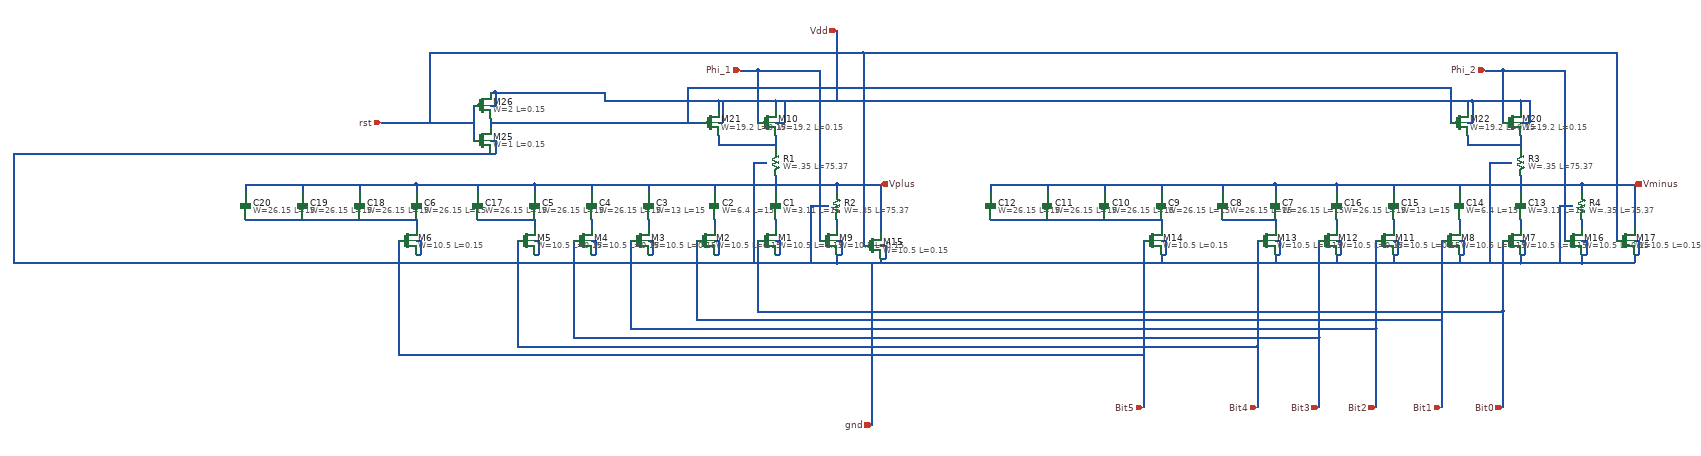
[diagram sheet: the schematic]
v {xschem version=3.4.6 file_version=1.2}
G {}
K {}
V {}
S {}
E {}
N -60 30 -60 70 {lab=Vplus}
N -200 50 -200 70 {lab=Vplus}
N -350 50 -350 70 {lab=Vplus}
N -480 50 -480 70 {lab=Vplus}
N -60 130 -60 150 {lab=#net1}
N -60 180 -50 180 {lab=gnd}
N -50 180 -50 210 {lab=gnd}
N -60 210 -50 210 {lab=gnd}
N -200 130 -200 150 {lab=#net2}
N -200 180 -190 180 {lab=gnd}
N -190 180 -190 210 {lab=gnd}
N -200 210 -190 210 {lab=gnd}
N -350 130 -350 150 {lab=#net3}
N -350 180 -340 180 {lab=gnd}
N -340 180 -340 210 {lab=gnd}
N -350 210 -340 210 {lab=gnd}
N -480 130 -480 150 {lab=#net4}
N -480 180 -470 180 {lab=gnd}
N -470 180 -470 210 {lab=gnd}
N -480 210 -470 210 {lab=gnd}
N -1060 230 -60 230 {lab=gnd}
N -60 230 80 230 {lab=gnd}
N 80 210 80 230 {lab=gnd}
N 80 210 90 210 {lab=gnd}
N 90 180 90 210 {lab=gnd}
N 80 180 90 180 {lab=gnd}
N 80 130 80 150 {lab=#net5}
N -520 180 -520 320 {lab=Bit3}
N -390 180 -390 320 {lab=Bit2}
N -240 180 -240 320 {lab=Bit1}
N -100 180 -100 320 {lab=Bit0}
N 80 50 80 70 {lab=Vplus}
N -60 50 80 50 {lab=Vplus}
N -60 -60 -60 -30 {lab=#net6}
N -60 -140 -60 -120 {lab=Vdd}
N 1640 30 1640 70 {lab=Vminus}
N 1500 50 1500 70 {lab=Vminus}
N 1350 50 1350 70 {lab=Vminus}
N 1220 50 1220 70 {lab=Vminus}
N 1640 130 1640 150 {lab=#net7}
N 1640 180 1650 180 {lab=gnd}
N 1650 180 1650 210 {lab=gnd}
N 1640 210 1650 210 {lab=gnd}
N 1500 130 1500 150 {lab=#net8}
N 1500 180 1510 180 {lab=gnd}
N 1510 180 1510 210 {lab=gnd}
N 1500 210 1510 210 {lab=gnd}
N 1350 130 1350 150 {lab=#net9}
N 1350 180 1360 180 {lab=gnd}
N 1360 180 1360 210 {lab=gnd}
N 1350 210 1360 210 {lab=gnd}
N 1220 130 1220 150 {lab=#net10}
N 1220 180 1230 180 {lab=gnd}
N 1230 180 1230 210 {lab=gnd}
N 1220 210 1230 210 {lab=gnd}
N 640 230 1640 230 {lab=gnd}
N 1220 210 1220 230 {lab=gnd}
N 1350 210 1350 230 {lab=gnd}
N 1500 210 1500 230 {lab=gnd}
N 1640 210 1640 230 {lab=gnd}
N 1640 230 1780 230 {lab=gnd}
N 1780 210 1780 230 {lab=gnd}
N 1780 210 1790 210 {lab=gnd}
N 1790 180 1790 210 {lab=gnd}
N 1780 180 1790 180 {lab=gnd}
N 1780 130 1780 150 {lab=#net11}
N 1180 180 1180 320 {lab=Bit3}
N 1310 180 1310 320 {lab=Bit2}
N 1460 180 1460 320 {lab=Bit1}
N 1600 180 1600 320 {lab=Bit0}
N 1780 50 1780 70 {lab=Vminus}
N 1640 50 1780 50 {lab=Vminus}
N 1640 -60 1640 -30 {lab=#net12}
N 1640 -140 1640 -120 {lab=Vdd}
N 80 230 300 230 {lab=gnd}
N -60 -140 1300 -140 {lab=Vdd}
N 80 -300 80 -140 {lab=Vdd}
N 160 230 160 560 {lab=gnd}
N 1600 320 1600 340 {lab=Bit0}
N -100 340 1260 340 {lab=Bit0}
N -100 320 -100 340 {lab=Bit0}
N 1460 320 1460 360 {lab=Bit1}
N -240 360 1120 360 {lab=Bit1}
N -240 320 -240 360 {lab=Bit1}
N 1310 320 1310 380 {lab=Bit2}
N -390 380 970 380 {lab=Bit2}
N -390 320 -390 380 {lab=Bit2}
N 1180 320 1180 400 {lab=Bit3}
N -520 400 840 400 {lab=Bit3}
N -520 320 -520 400 {lab=Bit3}
N 1180 400 1180 560 {lab=Bit3}
N 1310 380 1310 560 {lab=Bit2}
N 1460 360 1460 560 {lab=Bit1}
N 1600 340 1600 560 {lab=Bit0}
N 160 560 160 600 {lab=gnd}
N -60 -90 -40 -90 {lab=Vdd}
N -40 -140 -40 -90 {lab=Vdd}
N 1640 -90 1660 -90 {lab=Vdd}
N 1660 -140 1660 -90 {lab=Vdd}
N 1640 -140 1660 -140 {lab=Vdd}
N 1600 -210 1600 -90 {lab=Phi_2}
N 1600 -210 1740 -210 {lab=Phi_2}
N 1740 -210 1740 180 {lab=Phi_2}
N 1560 -210 1600 -210 {lab=Phi_2}
N 40 -210 40 180 {lab=Phi_1}
N -100 -210 40 -210 {lab=Phi_1}
N -100 -210 -100 -100 {lab=Phi_1}
N -140 -210 -100 -210 {lab=Phi_1}
N -100 -100 -100 -90 {lab=Phi_1}
N -110 -0 -80 -0 {lab=gnd}
N 20 100 60 100 {lab=gnd}
N 1730 100 1760 100 {lab=gnd}
N 1730 100 1730 230 {lab=gnd}
N 1570 0 1620 0 {lab=gnd}
N 1520 -140 1520 -120 {lab=Vdd}
N 1520 -90 1530 -90 {lab=Vdd}
N 1530 -140 1530 -90 {lab=Vdd}
N 1520 -60 1520 -40 {lab=#net12}
N 1520 -40 1640 -40 {lab=#net12}
N -190 -140 -60 -140 {lab=Vdd}
N -190 -90 -180 -90 {lab=Vdd}
N -180 -140 -180 -90 {lab=Vdd}
N -190 -140 -190 -120 {lab=Vdd}
N -190 -40 -60 -40 {lab=#net6}
N -190 -60 -190 -40 {lab=#net6}
N -280 -90 -230 -90 {lab=#net13}
N -260 -170 1140 -170 {lab=#net13}
N 1480 -170 1480 -90 {lab=#net13}
N 180 220 180 230 {lab=gnd}
N 180 190 190 190 {lab=gnd}
N 190 190 190 220 {lab=gnd}
N 180 220 190 220 {lab=gnd}
N 80 50 180 50 {lab=Vplus}
N 180 50 180 160 {lab=Vplus}
N 140 -250 140 190 {lab=rst}
N -280 -250 140 -250 {lab=rst}
N 1780 230 1900 230 {lab=gnd}
N 1900 210 1900 230 {lab=gnd}
N 1900 210 1910 210 {lab=gnd}
N 1910 180 1910 210 {lab=gnd}
N 1900 180 1910 180 {lab=gnd}
N 1900 50 1900 150 {lab=Vminus}
N 1780 50 1900 50 {lab=Vminus}
N 1860 -250 1860 180 {lab=rst}
N 140 -250 1520 -250 {lab=rst}
N -750 -130 -750 -50 {lab=rst}
N -960 -90 -750 -90 {lab=rst}
N -850 -250 -280 -250 {lab=rst}
N -850 -250 -850 -90 {lab=rst}
N -710 -100 -710 -80 {lab=#net13}
N -710 -90 -280 -90 {lab=#net13}
N -710 -130 -700 -130 {lab=Vdd}
N -700 -160 -700 -130 {lab=Vdd}
N -710 -160 -700 -160 {lab=Vdd}
N -710 -50 -700 -50 {lab=gnd}
N -700 -50 -700 -20 {lab=gnd}
N -710 -20 -700 -20 {lab=gnd}
N -1190 230 -1060 230 {lab=gnd}
N -1800 -20 -1800 230 {lab=gnd}
N -1190 -20 -710 -20 {lab=gnd}
N -700 -160 -450 -160 {lab=Vdd}
N -450 -160 -450 -140 {lab=Vdd}
N -450 -140 -190 -140 {lab=Vdd}
N -260 -170 -260 -90 {lab=#net13}
N -1360 -20 -1190 -20 {lab=gnd}
N -1360 230 -1190 230 {lab=gnd}
N 300 230 640 230 {lab=gnd}
N 1520 -250 1860 -250 {lab=rst}
N 1140 -170 1480 -170 {lab=#net13}
N 1300 -140 1530 -140 {lab=Vdd}
N 1530 -140 1640 -140 {lab=Vdd}
N 840 400 1180 400 {lab=Bit3}
N 970 380 1310 380 {lab=Bit2}
N 1120 360 1460 360 {lab=Bit1}
N 1260 340 1600 340 {lab=Bit0}
N -1800 -20 -1360 -20 {lab=gnd}
N -1800 230 -1360 230 {lab=gnd}
N 1220 50 1640 50 {lab=Vminus}
N -610 50 -610 70 {lab=Vplus}
N -600 50 -60 50 {lab=Vplus}
N -610 50 -600 50 {lab=Vplus}
N -610 180 -600 180 {lab=gnd}
N -600 180 -600 210 {lab=gnd}
N -610 210 -600 210 {lab=gnd}
N -610 130 -610 150 {lab=#net14}
N -650 180 -650 420 {lab=Bit4}
N -650 420 970 420 {lab=Bit4}
N 1080 50 1080 70 {lab=Vminus}
N 1080 180 1090 180 {lab=gnd}
N 1090 180 1090 210 {lab=gnd}
N 1080 210 1090 210 {lab=gnd}
N 1080 210 1080 230 {lab=gnd}
N 1080 130 1080 150 {lab=#net15}
N 1040 180 1040 420 {lab=Bit4}
N 970 420 1040 420 {lab=Bit4}
N 1040 420 1040 560 {lab=Bit4}
N 1080 50 1220 50 {lab=Vminus}
N -880 130 -880 150 {lab=#net16}
N -880 180 -870 180 {lab=gnd}
N -870 180 -870 210 {lab=gnd}
N -880 210 -870 210 {lab=gnd}
N -750 50 -610 50 {lab=Vplus}
N -880 50 -880 70 {lab=Vplus}
N -920 180 -920 440 {lab=Bit5}
N -790 440 690 440 {lab=Bit5}
N 1040 180 1040 420 {lab=Bit4}
N 820 130 820 150 {lab=#net17}
N 820 180 830 180 {lab=gnd}
N 830 180 830 210 {lab=gnd}
N 820 210 830 210 {lab=gnd}
N 820 210 820 230 {lab=gnd}
N 820 50 820 70 {lab=Vminus}
N 940 50 1080 50 {lab=Vminus}
N 960 50 960 70 {lab=Vminus}
N 960 130 1080 130 {lab=#net15}
N 430 130 820 130 {lab=#net17}
N 430 50 940 50 {lab=Vminus}
N 430 50 430 70 {lab=Vminus}
N 560 50 560 70 {lab=Vminus}
N 690 50 690 70 {lab=Vminus}
N 780 180 780 560 {lab=Bit5}
N 690 440 780 440 {lab=Bit5}
N -740 130 -610 130 {lab=#net14}
N -740 50 -740 70 {lab=Vplus}
N -920 440 -790 440 {lab=Bit5}
N -880 50 -750 50 {lab=Vplus}
N -1270 130 -880 130 {lab=#net16}
N -1270 50 -880 50 {lab=Vplus}
N -1270 50 -1270 70 {lab=Vplus}
N -1140 50 -1140 70 {lab=Vplus}
N -1010 50 -1010 70 {lab=Vplus}
N 1570 0 1570 230 {lab=gnd}
N -110 -0 -110 230 {lab=gnd}
N 20 100 20 230 {lab=gnd}
C {/usr/local/share/pdk/sky130A/libs.tech/xschem/sky130_fd_pr/cap_mim_m3_2.sym} -60 100 0 0 {name=C1 model=cap_mim_m3_2 W=3.11 L=15 MF=1 spiceprefix=X}
C {/usr/local/share/pdk/sky130A/libs.tech/xschem/sky130_fd_pr/cap_mim_m3_2.sym} -200 100 0 0 {name=C2 model=cap_mim_m3_2 W=6.4 L=15 MF=1 spiceprefix=X}
C {/usr/local/share/pdk/sky130A/libs.tech/xschem/sky130_fd_pr/cap_mim_m3_2.sym} -350 100 0 0 {name=C3 model=cap_mim_m3_2 W=13 L=15 MF=1 spiceprefix=X}
C {/usr/local/share/pdk/sky130A/libs.tech/xschem/sky130_fd_pr/cap_mim_m3_2.sym} -480 100 0 0 {name=C4 model=cap_mim_m3_2 W=26.15 L=15 MF=1 spiceprefix=X}
C {/usr/local/share/pdk/sky130A/libs.tech/xschem/sky130_fd_pr/nfet_01v8.sym} 60 180 0 0 {name=M9
W=10.5
L=0.15
nf=1 
mult=1
ad="'int((nf+1)/2) * W/nf * 0.29'" 
pd="'2*int((nf+1)/2) * (W/nf + 0.29)'"
as="'int((nf+2)/2) * W/nf * 0.29'" 
ps="'2*int((nf+2)/2) * (W/nf + 0.29)'"
nrd="'0.29 / W'" nrs="'0.29 / W'"
sa=0 sb=0 sd=0
model=nfet_01v8
spiceprefix=X
}
C {/usr/local/share/pdk/sky130A/libs.tech/xschem/sky130_fd_pr/pfet_01v8.sym} -80 -90 0 0 {name=M10
W=19.2
L=0.15
nf=1
mult=1
ad="'int((nf+1)/2) * W/nf * 0.29'" 
pd="'2*int((nf+1)/2) * (W/nf + 0.29)'"
as="'int((nf+2)/2) * W/nf * 0.29'" 
ps="'2*int((nf+2)/2) * (W/nf + 0.29)'"
nrd="'0.29 / W'" nrs="'0.29 / W'"
sa=0 sb=0 sd=0
model=pfet_01v8
spiceprefix=X
}
C {/usr/local/share/pdk/sky130A/libs.tech/xschem/sky130_fd_pr/pfet_01v8.sym} 1620 -90 0 0 {name=M20
W=19.2
L=0.15
nf=1
mult=1
ad="'int((nf+1)/2) * W/nf * 0.29'" 
pd="'2*int((nf+1)/2) * (W/nf + 0.29)'"
as="'int((nf+2)/2) * W/nf * 0.29'" 
ps="'2*int((nf+2)/2) * (W/nf + 0.29)'"
nrd="'0.29 / W'" nrs="'0.29 / W'"
sa=0 sb=0 sd=0
model=pfet_01v8
spiceprefix=X
}
C {opin.sym} 180 50 0 0 {name=p1 lab=Vplus}
C {opin.sym} 1900 50 0 0 {name=p2 lab=Vminus}
C {iopin.sym} 80 -300 0 0 {name=p3 lab=Vdd}
C {iopin.sym} 160 600 0 0 {name=p4 lab=gnd
}
C {ipin.sym} -140 -210 0 0 {name=p5 lab=Phi_1}
C {ipin.sym} 1560 -210 0 0 {name=p6 lab=Phi_2}
C {ipin.sym} 1600 560 0 0 {name=p7 lab=Bit0}
C {ipin.sym} 1460 560 0 0 {name=p8 lab=Bit1}
C {ipin.sym} 1310 560 0 0 {name=p9 lab=Bit2}
C {ipin.sym} 1180 560 0 0 {name=p10 lab=Bit3}
C {/usr/local/share/pdk/sky130A/libs.tech/xschem/sky130_fd_pr/pfet_01v8.sym} -210 -90 0 0 {name=M21
W=19.2
L=0.15
nf=1
mult=1
ad="'int((nf+1)/2) * W/nf * 0.29'" 
pd="'2*int((nf+1)/2) * (W/nf + 0.29)'"
as="'int((nf+2)/2) * W/nf * 0.29'" 
ps="'2*int((nf+2)/2) * (W/nf + 0.29)'"
nrd="'0.29 / W'" nrs="'0.29 / W'"
sa=0 sb=0 sd=0
model=pfet_01v8
spiceprefix=X
}
C {/usr/local/share/pdk/sky130A/libs.tech/xschem/sky130_fd_pr/pfet_01v8.sym} 1500 -90 0 0 {name=M22
W=19.2
L=0.15
nf=1
mult=1
ad="'int((nf+1)/2) * W/nf * 0.29'" 
pd="'2*int((nf+1)/2) * (W/nf + 0.29)'"
as="'int((nf+2)/2) * W/nf * 0.29'" 
ps="'2*int((nf+2)/2) * (W/nf + 0.29)'"
nrd="'0.29 / W'" nrs="'0.29 / W'"
sa=0 sb=0 sd=0
model=pfet_01v8
spiceprefix=X
}
C {/usr/local/share/pdk/sky130A/libs.tech/xschem/sky130_fd_pr/nfet_01v8.sym} -730 -50 0 0 {name=M25
W=1
L=0.15
nf=1 
mult=1
ad="'int((nf+1)/2) * W/nf * 0.29'" 
pd="'2*int((nf+1)/2) * (W/nf + 0.29)'"
as="'int((nf+2)/2) * W/nf * 0.29'" 
ps="'2*int((nf+2)/2) * (W/nf + 0.29)'"
nrd="'0.29 / W'" nrs="'0.29 / W'"
sa=0 sb=0 sd=0
model=nfet_01v8
spiceprefix=X
}
C {/usr/local/share/pdk/sky130A/libs.tech/xschem/sky130_fd_pr/pfet_01v8.sym} -730 -130 0 0 {name=M26
W=2
L=0.15
nf=1
mult=1
ad="'int((nf+1)/2) * W/nf * 0.29'" 
pd="'2*int((nf+1)/2) * (W/nf + 0.29)'"
as="'int((nf+2)/2) * W/nf * 0.29'" 
ps="'2*int((nf+2)/2) * (W/nf + 0.29)'"
nrd="'0.29 / W'" nrs="'0.29 / W'"
sa=0 sb=0 sd=0
model=pfet_01v8
spiceprefix=X
}
C {ipin.sym} -960 -90 0 0 {name=p15 lab=rst}
C {ipin.sym} 1040 560 0 0 {name=p11 lab=Bit4}
C {ipin.sym} 780 560 0 0 {name=p12 lab=Bit5}
C {/usr/local/share/pdk/sky130A/libs.tech/xschem/sky130_fd_pr/cap_mim_m3_2.sym} 1640 100 0 0 {name=C13 model=cap_mim_m3_2 W=3.11 L=15 MF=1 spiceprefix=X}
C {/usr/local/share/pdk/sky130A/libs.tech/xschem/sky130_fd_pr/cap_mim_m3_2.sym} 1500 100 0 0 {name=C14 model=cap_mim_m3_2 W=6.4 L=15 MF=1 spiceprefix=X}
C {/usr/local/share/pdk/sky130A/libs.tech/xschem/sky130_fd_pr/cap_mim_m3_2.sym} 1350 100 0 0 {name=C15 model=cap_mim_m3_2 W=13 L=15 MF=1 spiceprefix=X}
C {/usr/local/share/pdk/sky130A/libs.tech/xschem/sky130_fd_pr/cap_mim_m3_2.sym} 1220 100 0 0 {name=C16 model=cap_mim_m3_2 W=26.15 L=15 MF=1 spiceprefix=X}
C {/usr/local/share/pdk/sky130A/libs.tech/xschem/sky130_fd_pr/nfet_01v8.sym} -80 180 0 0 {name=M1
W=10.5
L=0.15
nf=1 
mult=1
ad="'int((nf+1)/2) * W/nf * 0.29'" 
pd="'2*int((nf+1)/2) * (W/nf + 0.29)'"
as="'int((nf+2)/2) * W/nf * 0.29'" 
ps="'2*int((nf+2)/2) * (W/nf + 0.29)'"
nrd="'0.29 / W'" nrs="'0.29 / W'"
sa=0 sb=0 sd=0
model=nfet_01v8
spiceprefix=X
}
C {/usr/local/share/pdk/sky130A/libs.tech/xschem/sky130_fd_pr/nfet_01v8.sym} -220 180 0 0 {name=M2
W=10.5
L=0.15
nf=1 
mult=1
ad="'int((nf+1)/2) * W/nf * 0.29'" 
pd="'2*int((nf+1)/2) * (W/nf + 0.29)'"
as="'int((nf+2)/2) * W/nf * 0.29'" 
ps="'2*int((nf+2)/2) * (W/nf + 0.29)'"
nrd="'0.29 / W'" nrs="'0.29 / W'"
sa=0 sb=0 sd=0
model=nfet_01v8
spiceprefix=X
}
C {/usr/local/share/pdk/sky130A/libs.tech/xschem/sky130_fd_pr/nfet_01v8.sym} -370 180 0 0 {name=M3
W=10.5
L=0.15
nf=1 
mult=1
ad="'int((nf+1)/2) * W/nf * 0.29'" 
pd="'2*int((nf+1)/2) * (W/nf + 0.29)'"
as="'int((nf+2)/2) * W/nf * 0.29'" 
ps="'2*int((nf+2)/2) * (W/nf + 0.29)'"
nrd="'0.29 / W'" nrs="'0.29 / W'"
sa=0 sb=0 sd=0
model=nfet_01v8
spiceprefix=X
}
C {/usr/local/share/pdk/sky130A/libs.tech/xschem/sky130_fd_pr/nfet_01v8.sym} -500 180 0 0 {name=M4
W=10.5
L=0.15
nf=1 
mult=1
ad="'int((nf+1)/2) * W/nf * 0.29'" 
pd="'2*int((nf+1)/2) * (W/nf + 0.29)'"
as="'int((nf+2)/2) * W/nf * 0.29'" 
ps="'2*int((nf+2)/2) * (W/nf + 0.29)'"
nrd="'0.29 / W'" nrs="'0.29 / W'"
sa=0 sb=0 sd=0
model=nfet_01v8
spiceprefix=X
}
C {/usr/local/share/pdk/sky130A/libs.tech/xschem/sky130_fd_pr/nfet_01v8.sym} -630 180 0 0 {name=M5
W=10.5
L=0.15
nf=1 
mult=1
ad="'int((nf+1)/2) * W/nf * 0.29'" 
pd="'2*int((nf+1)/2) * (W/nf + 0.29)'"
as="'int((nf+2)/2) * W/nf * 0.29'" 
ps="'2*int((nf+2)/2) * (W/nf + 0.29)'"
nrd="'0.29 / W'" nrs="'0.29 / W'"
sa=0 sb=0 sd=0
model=nfet_01v8
spiceprefix=X
}
C {/usr/local/share/pdk/sky130A/libs.tech/xschem/sky130_fd_pr/nfet_01v8.sym} -900 180 0 0 {name=M6
W=10.5
L=0.15
nf=1 
mult=1
ad="'int((nf+1)/2) * W/nf * 0.29'" 
pd="'2*int((nf+1)/2) * (W/nf + 0.29)'"
as="'int((nf+2)/2) * W/nf * 0.29'" 
ps="'2*int((nf+2)/2) * (W/nf + 0.29)'"
nrd="'0.29 / W'" nrs="'0.29 / W'"
sa=0 sb=0 sd=0
model=nfet_01v8
spiceprefix=X
}
C {/usr/local/share/pdk/sky130A/libs.tech/xschem/sky130_fd_pr/nfet_01v8.sym} 160 190 0 0 {name=M15
W=10.5
L=0.15
nf=1 
mult=1
ad="'int((nf+1)/2) * W/nf * 0.29'" 
pd="'2*int((nf+1)/2) * (W/nf + 0.29)'"
as="'int((nf+2)/2) * W/nf * 0.29'" 
ps="'2*int((nf+2)/2) * (W/nf + 0.29)'"
nrd="'0.29 / W'" nrs="'0.29 / W'"
sa=0 sb=0 sd=0
model=nfet_01v8
spiceprefix=X
}
C {/usr/local/share/pdk/sky130A/libs.tech/xschem/sky130_fd_pr/nfet_01v8.sym} 1620 180 0 0 {name=M7
W=10.5
L=0.15
nf=1 
mult=1
ad="'int((nf+1)/2) * W/nf * 0.29'" 
pd="'2*int((nf+1)/2) * (W/nf + 0.29)'"
as="'int((nf+2)/2) * W/nf * 0.29'" 
ps="'2*int((nf+2)/2) * (W/nf + 0.29)'"
nrd="'0.29 / W'" nrs="'0.29 / W'"
sa=0 sb=0 sd=0
model=nfet_01v8
spiceprefix=X
}
C {/usr/local/share/pdk/sky130A/libs.tech/xschem/sky130_fd_pr/nfet_01v8.sym} 1480 180 0 0 {name=M8
W=10.5
L=0.15
nf=1 
mult=1
ad="'int((nf+1)/2) * W/nf * 0.29'" 
pd="'2*int((nf+1)/2) * (W/nf + 0.29)'"
as="'int((nf+2)/2) * W/nf * 0.29'" 
ps="'2*int((nf+2)/2) * (W/nf + 0.29)'"
nrd="'0.29 / W'" nrs="'0.29 / W'"
sa=0 sb=0 sd=0
model=nfet_01v8
spiceprefix=X
}
C {/usr/local/share/pdk/sky130A/libs.tech/xschem/sky130_fd_pr/nfet_01v8.sym} 1330 180 0 0 {name=M11
W=10.5
L=0.15
nf=1 
mult=1
ad="'int((nf+1)/2) * W/nf * 0.29'" 
pd="'2*int((nf+1)/2) * (W/nf + 0.29)'"
as="'int((nf+2)/2) * W/nf * 0.29'" 
ps="'2*int((nf+2)/2) * (W/nf + 0.29)'"
nrd="'0.29 / W'" nrs="'0.29 / W'"
sa=0 sb=0 sd=0
model=nfet_01v8
spiceprefix=X
}
C {/usr/local/share/pdk/sky130A/libs.tech/xschem/sky130_fd_pr/nfet_01v8.sym} 1200 180 0 0 {name=M12
W=10.5
L=0.15
nf=1 
mult=1
ad="'int((nf+1)/2) * W/nf * 0.29'" 
pd="'2*int((nf+1)/2) * (W/nf + 0.29)'"
as="'int((nf+2)/2) * W/nf * 0.29'" 
ps="'2*int((nf+2)/2) * (W/nf + 0.29)'"
nrd="'0.29 / W'" nrs="'0.29 / W'"
sa=0 sb=0 sd=0
model=nfet_01v8
spiceprefix=X
}
C {/usr/local/share/pdk/sky130A/libs.tech/xschem/sky130_fd_pr/nfet_01v8.sym} 1060 180 0 0 {name=M13
W=10.5
L=0.15
nf=1 
mult=1
ad="'int((nf+1)/2) * W/nf * 0.29'" 
pd="'2*int((nf+1)/2) * (W/nf + 0.29)'"
as="'int((nf+2)/2) * W/nf * 0.29'" 
ps="'2*int((nf+2)/2) * (W/nf + 0.29)'"
nrd="'0.29 / W'" nrs="'0.29 / W'"
sa=0 sb=0 sd=0
model=nfet_01v8
spiceprefix=X
}
C {/usr/local/share/pdk/sky130A/libs.tech/xschem/sky130_fd_pr/nfet_01v8.sym} 800 180 0 0 {name=M14
W=10.5
L=0.15
nf=1 
mult=1
ad="'int((nf+1)/2) * W/nf * 0.29'" 
pd="'2*int((nf+1)/2) * (W/nf + 0.29)'"
as="'int((nf+2)/2) * W/nf * 0.29'" 
ps="'2*int((nf+2)/2) * (W/nf + 0.29)'"
nrd="'0.29 / W'" nrs="'0.29 / W'"
sa=0 sb=0 sd=0
model=nfet_01v8
spiceprefix=X
}
C {/usr/local/share/pdk/sky130A/libs.tech/xschem/sky130_fd_pr/nfet_01v8.sym} 1760 180 0 0 {name=M16
W=10.5
L=0.15
nf=1 
mult=1
ad="'int((nf+1)/2) * W/nf * 0.29'" 
pd="'2*int((nf+1)/2) * (W/nf + 0.29)'"
as="'int((nf+2)/2) * W/nf * 0.29'" 
ps="'2*int((nf+2)/2) * (W/nf + 0.29)'"
nrd="'0.29 / W'" nrs="'0.29 / W'"
sa=0 sb=0 sd=0
model=nfet_01v8
spiceprefix=X
}
C {/usr/local/share/pdk/sky130A/libs.tech/xschem/sky130_fd_pr/nfet_01v8.sym} 1880 180 0 0 {name=M17
W=10.5
L=0.15
nf=1 
mult=1
ad="'int((nf+1)/2) * W/nf * 0.29'" 
pd="'2*int((nf+1)/2) * (W/nf + 0.29)'"
as="'int((nf+2)/2) * W/nf * 0.29'" 
ps="'2*int((nf+2)/2) * (W/nf + 0.29)'"
nrd="'0.29 / W'" nrs="'0.29 / W'"
sa=0 sb=0 sd=0
model=nfet_01v8
spiceprefix=X
}
C {/usr/local/share/pdk/sky130A/libs.tech/xschem/sky130_fd_pr/cap_mim_m3_2.sym} -610 100 0 0 {name=C5 model=cap_mim_m3_2 W=26.15 L=15 MF=1 spiceprefix=X}
C {/usr/local/share/pdk/sky130A/libs.tech/xschem/sky130_fd_pr/cap_mim_m3_2.sym} 1080 100 0 0 {name=C7 model=cap_mim_m3_2 W=26.15 L=15 MF=1 spiceprefix=X}
C {/usr/local/share/pdk/sky130A/libs.tech/xschem/sky130_fd_pr/cap_mim_m3_2.sym} 960 100 0 0 {name=C8 model=cap_mim_m3_2 W=26.15 L=15 MF=1 spiceprefix=X}
C {/usr/local/share/pdk/sky130A/libs.tech/xschem/sky130_fd_pr/cap_mim_m3_2.sym} 820 100 0 0 {name=C9 model=cap_mim_m3_2 W=26.15 L=15 MF=1 spiceprefix=X}
C {/usr/local/share/pdk/sky130A/libs.tech/xschem/sky130_fd_pr/cap_mim_m3_2.sym} 690 100 0 0 {name=C10 model=cap_mim_m3_2 W=26.15 L=15 MF=1 spiceprefix=X}
C {/usr/local/share/pdk/sky130A/libs.tech/xschem/sky130_fd_pr/cap_mim_m3_2.sym} 560 100 0 0 {name=C11 model=cap_mim_m3_2 W=26.15 L=15 MF=1 spiceprefix=X}
C {/usr/local/share/pdk/sky130A/libs.tech/xschem/sky130_fd_pr/cap_mim_m3_2.sym} 430 100 0 0 {name=C12 model=cap_mim_m3_2 W=26.15 L=15 MF=1 spiceprefix=X}
C {/usr/local/share/pdk/sky130A/libs.tech/xschem/sky130_fd_pr/cap_mim_m3_2.sym} -740 100 0 0 {name=C17 model=cap_mim_m3_2 W=26.15 L=15 MF=1 spiceprefix=X}
C {/usr/local/share/pdk/sky130A/libs.tech/xschem/sky130_fd_pr/cap_mim_m3_2.sym} -1010 100 0 0 {name=C18 model=cap_mim_m3_2 W=26.15 L=15 MF=1 spiceprefix=X}
C {/usr/local/share/pdk/sky130A/libs.tech/xschem/sky130_fd_pr/cap_mim_m3_2.sym} -880 100 0 0 {name=C6 model=cap_mim_m3_2 W=26.15 L=15 MF=1 spiceprefix=X}
C {/usr/local/share/pdk/sky130A/libs.tech/xschem/sky130_fd_pr/cap_mim_m3_2.sym} -1140 100 0 0 {name=C19 model=cap_mim_m3_2 W=26.15 L=15 MF=1 spiceprefix=X}
C {/usr/local/share/pdk/sky130A/libs.tech/xschem/sky130_fd_pr/cap_mim_m3_2.sym} -1270 100 0 0 {name=C20 model=cap_mim_m3_2 W=26.15 L=15 MF=1 spiceprefix=X}
C {/usr/local/share/pdk/sky130A/libs.tech/xschem/sky130_fd_pr/res_xhigh_po.sym} -60 0 0 0 {name=R1
W=.35
L=75.37
model=res_xhigh_po
spiceprefix=X
mult=1}
C {/usr/local/share/pdk/sky130A/libs.tech/xschem/sky130_fd_pr/res_xhigh_po.sym} 80 100 0 0 {name=R2
W=.35
L=75.37
model=res_xhigh_po
spiceprefix=X
mult=1}
C {/usr/local/share/pdk/sky130A/libs.tech/xschem/sky130_fd_pr/res_xhigh_po.sym} 1640 0 0 0 {name=R3
W=.35
L=75.37
model=res_xhigh_po
spiceprefix=X
mult=1}
C {/usr/local/share/pdk/sky130A/libs.tech/xschem/sky130_fd_pr/res_xhigh_po.sym} 1780 100 0 0 {name=R4
W=.35
L=75.37
model=res_xhigh_po
spiceprefix=X
mult=1}
